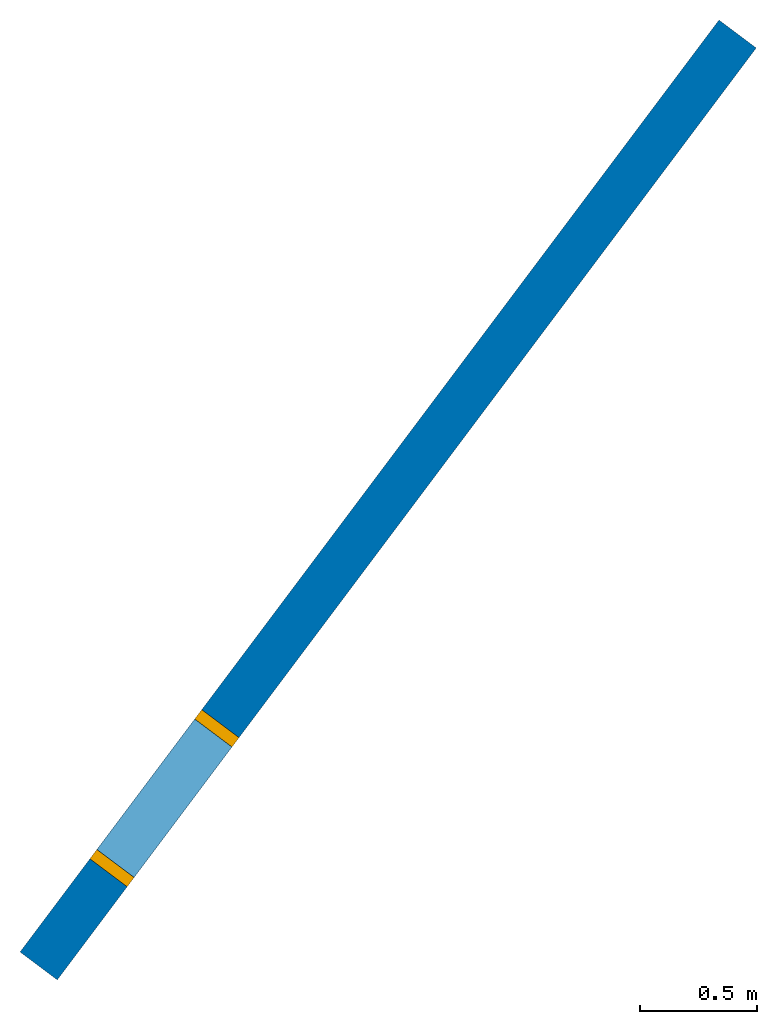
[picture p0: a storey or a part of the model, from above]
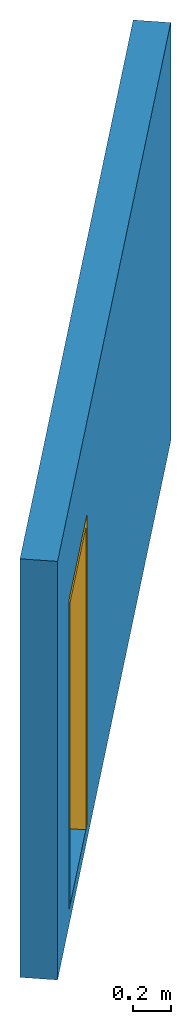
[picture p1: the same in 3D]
Properties of the parts of a building model (IFC4)

# File
Description: 3117 native IFC4 snapshot; straight uniform walls and generic hosted door frames, Source content revision: 31b79c638cc70358bb6d8fa92005a1922ca7fd248332650582ce19d636da6cf0
Time: 2026-10-22T23:10:51
Author: 3117 BIM
Written by: IfcOpenShell 0.8.4
Made in: 3117 BIM Studio 0.2.1

# IfcProject, 3117 ปริมาณและ IFC
LongName: QTY-003
BIM3117_Source - ContentRevision: 31b79c638cc70358bb6d8fa92005a1922ca7fd248332650582ce19d636da6cf0; NativeObjectName: BIM3117_Project; SourceModel: FreeCAD Document / FCStd; WorkbenchVersion: 0.2.1; ProjectNumber: QTY-003; Author: 3117 BIM; RevisionMeaning: SHA-256 content identity; Undo may restore an earlier identity; QuantityRule: Straight uniform walls, one side; openings deducted; wall joins excluded; CoverageComplete: no

# IfcSite, 3117 Site
BIM3117_Source - ContentRevision: 31b79c638cc70358bb6d8fa92005a1922ca7fd248332650582ce19d636da6cf0; Mapping: Generated local site container; no survey/georeferencing claimed

# IfcBuilding, 3117 ปริมาณและ IFC
BIM3117_Source - ContentRevision: 31b79c638cc70358bb6d8fa92005a1922ca7fd248332650582ce19d636da6cf0; Mapping: Generated building container for the single native Project

# IfcBuildingStorey (3)
In: 3117 ปริมาณและ IFC
BIM3117_Source - ContentRevision: 31b79c638cc70358bb6d8fa92005a1922ca7fd248332650582ce19d636da6cf0; SourceModel: FreeCAD Document / FCStd; WorkbenchVersion: 0.2.1
Name | Elevation (m) | NativeObjectName
B01 | -3 | BIM3117_Level002
L00 | 0 | BIM3117_Level
L01 | 3 | BIM3117_Level001

# IfcDoor (3)
PredefinedType: DOOR
BIM3117_Source - ContentRevision: 31b79c638cc70358bb6d8fa92005a1922ca7fd248332650582ce19d636da6cf0; SourceModel: FreeCAD Document / FCStd; WorkbenchVersion: 0.2.1; Geometry: Generic three-bar frame, no leaf/handing/swing; DimensionMeaning: Overall wall-cut opening including frame; not clear passage or leaf
Name | In | OverallHeight (m) | OverallWidth (m) | NativeObjectName | OffsetM | SillM | FrameVolumeM3
Basement door | B01 | 2 | 0.8 | BIM3117_Door001 | 0.5 | 0.1 | 0.047
Reversed door | L00 | 2.1 | 0.8 | BIM3117_Door002 | 0.7 | 0 | 0.049
ประตู D01 | L00 | 2.1 | 0.9 | BIM3117_Door | 1.2 | 0 | 0.05

# IfcOpeningElement (3)
PredefinedType: OPENING
BIM3117_Source - ContentRevision: 31b79c638cc70358bb6d8fa92005a1922ca7fd248332650582ce19d636da6cf0; BooleanPaddingM: 0.000001
Name | In
Opening — Basement door | B01
Opening — Reversed door | L00
Opening — ประตู D01 | L00

# IfcWall: W200 (3)
Type - PredefinedType: STANDARD; Material: Concrete
Type - BIM3117_Source - ContentRevision: 31b79c638cc70358bb6d8fa92005a1922ca7fd248332650582ce19d636da6cf0; NativeObjectName: BIM3117_WallType; SourceModel: FreeCAD Document / FCStd; WorkbenchVersion: 0.2.1; ThicknessM: 0.2; MaterialDescription: Concrete; Assembly: Uniform wall; no material layer assembly
BIM3117_Source - QuantityRule: One wall, one side; actual cut solid; no wall joins/layers
Qto_WallBaseQuantities - Width: 0.2 m
Name | In | NativeObjectName | BaseOffsetM | TopOffsetM | Length (m) | Height (m) | GrossSideArea (m2) | NetSideArea (m2) | GrossVolume (m3) | NetVolume (m3)
Diagonal basement | B01 | BIM3117_Wall001 | 0.1 | -0.2 | 5 | 2.7 | 13.5 | 11.9 | 2.7 | 2.38
W201 | L00 | BIM3117_Wall | 0 | 0 | 6 | 3 | 18 | 16.11 | 3.6 | 3.222
Reversed wall | L00 | BIM3117_Wall002 | 0 | 0 | 4 | 3 | 12 | 10.32 | 2.4 | 2.064
